VERSION 5.7 ;
  NOWIREEXTENSIONATPIN ON ;
  DIVIDERCHAR "/" ;
  BUSBITCHARS "[]" ;
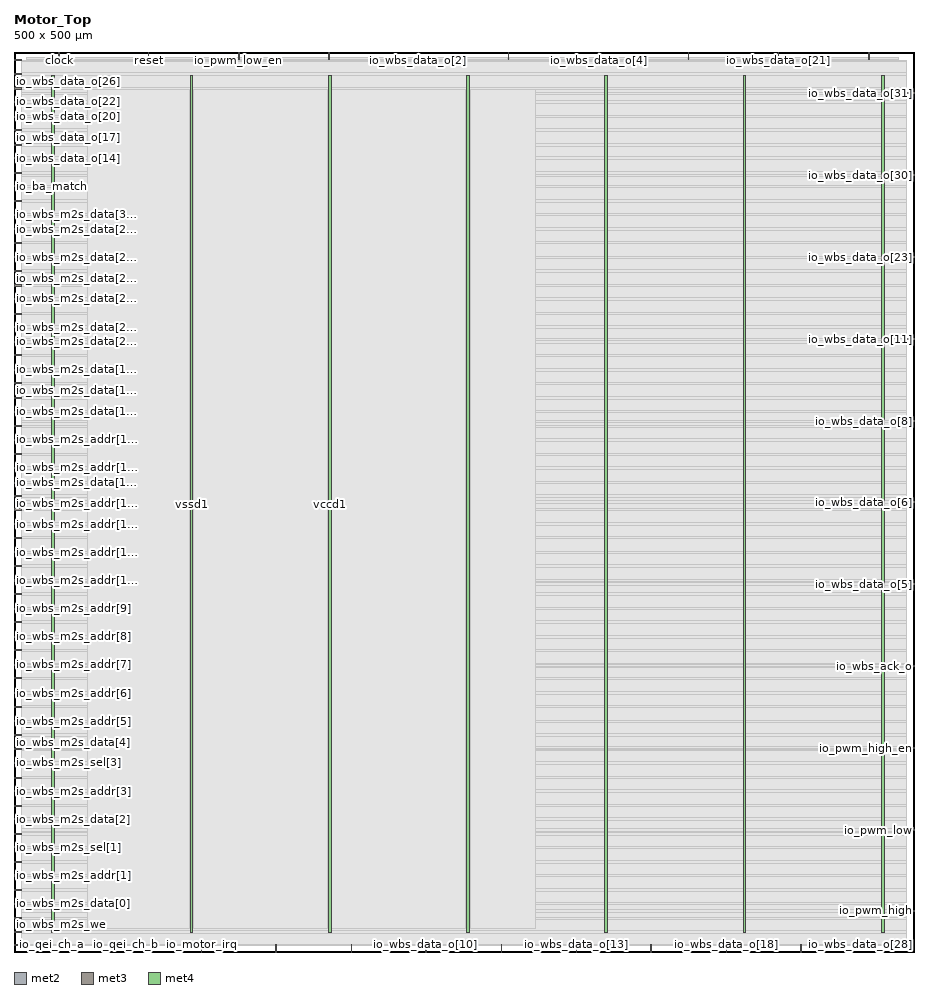
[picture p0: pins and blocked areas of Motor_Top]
MACRO Motor_Top
  CLASS BLOCK ;
  FOREIGN Motor_Top ;
  ORIGIN 0.000 0.000 ;
  SIZE 500.000 BY 500.000 ;
  PIN clock
    DIRECTION INPUT ;
    USE SIGNAL ;
    PORT
      LAYER met2 ;
        RECT 24.930 496.000 25.210 500.000 ;
    END
  END clock
  PIN io_ba_match
    DIRECTION INPUT ;
    USE SIGNAL ;
    PORT
      LAYER met3 ;
        RECT 0.000 425.040 4.000 425.640 ;
    END
  END io_ba_match
  PIN io_motor_irq
    DIRECTION OUTPUT TRISTATE ;
    USE SIGNAL ;
    PORT
      LAYER met2 ;
        RECT 104.050 0.000 104.330 4.000 ;
    END
  END io_motor_irq
  PIN io_pwm_high
    DIRECTION OUTPUT TRISTATE ;
    USE SIGNAL ;
    PORT
      LAYER met3 ;
        RECT 496.000 22.480 500.000 23.080 ;
    END
  END io_pwm_high
  PIN io_pwm_high_en
    DIRECTION OUTPUT TRISTATE ;
    USE SIGNAL ;
    PORT
      LAYER met3 ;
        RECT 496.000 112.920 500.000 113.520 ;
    END
  END io_pwm_high_en
  PIN io_pwm_low
    DIRECTION OUTPUT TRISTATE ;
    USE SIGNAL ;
    PORT
      LAYER met3 ;
        RECT 496.000 67.360 500.000 67.960 ;
    END
  END io_pwm_low
  PIN io_pwm_low_en
    DIRECTION OUTPUT TRISTATE ;
    USE SIGNAL ;
    PORT
      LAYER met2 ;
        RECT 124.750 496.000 125.030 500.000 ;
    END
  END io_pwm_low_en
  PIN io_qei_ch_a
    DIRECTION INPUT ;
    USE SIGNAL ;
    PORT
      LAYER met2 ;
        RECT 20.790 0.000 21.070 4.000 ;
    END
  END io_qei_ch_a
  PIN io_qei_ch_b
    DIRECTION INPUT ;
    USE SIGNAL ;
    PORT
      LAYER met2 ;
        RECT 62.190 0.000 62.470 4.000 ;
    END
  END io_qei_ch_b
  PIN io_wbs_ack_o
    DIRECTION OUTPUT TRISTATE ;
    USE SIGNAL ;
    PORT
      LAYER met3 ;
        RECT 496.000 158.480 500.000 159.080 ;
    END
  END io_wbs_ack_o
  PIN io_wbs_data_o[0]
    DIRECTION OUTPUT TRISTATE ;
    USE SIGNAL ;
    PORT
      LAYER met2 ;
        RECT 174.890 496.000 175.170 500.000 ;
    END
  END io_wbs_data_o[0]
  PIN io_wbs_data_o[10]
    DIRECTION OUTPUT TRISTATE ;
    USE SIGNAL ;
    PORT
      LAYER met2 ;
        RECT 228.710 0.000 228.990 4.000 ;
    END
  END io_wbs_data_o[10]
  PIN io_wbs_data_o[11]
    DIRECTION OUTPUT TRISTATE ;
    USE SIGNAL ;
    PORT
      LAYER met3 ;
        RECT 496.000 340.040 500.000 340.640 ;
    END
  END io_wbs_data_o[11]
  PIN io_wbs_data_o[12]
    DIRECTION OUTPUT TRISTATE ;
    USE SIGNAL ;
    PORT
      LAYER met2 ;
        RECT 270.570 0.000 270.850 4.000 ;
    END
  END io_wbs_data_o[12]
  PIN io_wbs_data_o[13]
    DIRECTION OUTPUT TRISTATE ;
    USE SIGNAL ;
    PORT
      LAYER met2 ;
        RECT 312.430 0.000 312.710 4.000 ;
    END
  END io_wbs_data_o[13]
  PIN io_wbs_data_o[14]
    DIRECTION OUTPUT TRISTATE ;
    USE SIGNAL ;
    PORT
      LAYER met3 ;
        RECT 0.000 440.680 4.000 441.280 ;
    END
  END io_wbs_data_o[14]
  PIN io_wbs_data_o[15]
    DIRECTION OUTPUT TRISTATE ;
    USE SIGNAL ;
    PORT
      LAYER met2 ;
        RECT 374.530 496.000 374.810 500.000 ;
    END
  END io_wbs_data_o[15]
  PIN io_wbs_data_o[16]
    DIRECTION OUTPUT TRISTATE ;
    USE SIGNAL ;
    PORT
      LAYER met2 ;
        RECT 353.830 0.000 354.110 4.000 ;
    END
  END io_wbs_data_o[16]
  PIN io_wbs_data_o[17]
    DIRECTION OUTPUT TRISTATE ;
    USE SIGNAL ;
    PORT
      LAYER met3 ;
        RECT 0.000 448.160 4.000 448.760 ;
    END
  END io_wbs_data_o[17]
  PIN io_wbs_data_o[18]
    DIRECTION OUTPUT TRISTATE ;
    USE SIGNAL ;
    PORT
      LAYER met2 ;
        RECT 395.690 0.000 395.970 4.000 ;
    END
  END io_wbs_data_o[18]
  PIN io_wbs_data_o[19]
    DIRECTION OUTPUT TRISTATE ;
    USE SIGNAL ;
    PORT
      LAYER met3 ;
        RECT 0.000 456.320 4.000 456.920 ;
    END
  END io_wbs_data_o[19]
  PIN io_wbs_data_o[1]
    DIRECTION OUTPUT TRISTATE ;
    USE SIGNAL ;
    PORT
      LAYER met3 ;
        RECT 0.000 432.520 4.000 433.120 ;
    END
  END io_wbs_data_o[1]
  PIN io_wbs_data_o[20]
    DIRECTION OUTPUT TRISTATE ;
    USE SIGNAL ;
    PORT
      LAYER met3 ;
        RECT 0.000 463.800 4.000 464.400 ;
    END
  END io_wbs_data_o[20]
  PIN io_wbs_data_o[21]
    DIRECTION OUTPUT TRISTATE ;
    USE SIGNAL ;
    PORT
      LAYER met2 ;
        RECT 424.670 496.000 424.950 500.000 ;
    END
  END io_wbs_data_o[21]
  PIN io_wbs_data_o[22]
    DIRECTION OUTPUT TRISTATE ;
    USE SIGNAL ;
    PORT
      LAYER met3 ;
        RECT 0.000 471.960 4.000 472.560 ;
    END
  END io_wbs_data_o[22]
  PIN io_wbs_data_o[23]
    DIRECTION OUTPUT TRISTATE ;
    USE SIGNAL ;
    PORT
      LAYER met3 ;
        RECT 496.000 385.600 500.000 386.200 ;
    END
  END io_wbs_data_o[23]
  PIN io_wbs_data_o[24]
    DIRECTION OUTPUT TRISTATE ;
    USE SIGNAL ;
    PORT
      LAYER met2 ;
        RECT 437.090 0.000 437.370 4.000 ;
    END
  END io_wbs_data_o[24]
  PIN io_wbs_data_o[25]
    DIRECTION OUTPUT TRISTATE ;
    USE SIGNAL ;
    PORT
      LAYER met3 ;
        RECT 0.000 479.440 4.000 480.040 ;
    END
  END io_wbs_data_o[25]
  PIN io_wbs_data_o[26]
    DIRECTION OUTPUT TRISTATE ;
    USE SIGNAL ;
    PORT
      LAYER met3 ;
        RECT 0.000 487.600 4.000 488.200 ;
    END
  END io_wbs_data_o[26]
  PIN io_wbs_data_o[27]
    DIRECTION OUTPUT TRISTATE ;
    USE SIGNAL ;
    PORT
      LAYER met3 ;
        RECT 0.000 495.080 4.000 495.680 ;
    END
  END io_wbs_data_o[27]
  PIN io_wbs_data_o[28]
    DIRECTION OUTPUT TRISTATE ;
    USE SIGNAL ;
    PORT
      LAYER met2 ;
        RECT 478.950 0.000 479.230 4.000 ;
    END
  END io_wbs_data_o[28]
  PIN io_wbs_data_o[29]
    DIRECTION OUTPUT TRISTATE ;
    USE SIGNAL ;
    PORT
      LAYER met2 ;
        RECT 474.810 496.000 475.090 500.000 ;
    END
  END io_wbs_data_o[29]
  PIN io_wbs_data_o[2]
    DIRECTION OUTPUT TRISTATE ;
    USE SIGNAL ;
    PORT
      LAYER met2 ;
        RECT 224.570 496.000 224.850 500.000 ;
    END
  END io_wbs_data_o[2]
  PIN io_wbs_data_o[30]
    DIRECTION OUTPUT TRISTATE ;
    USE SIGNAL ;
    PORT
      LAYER met3 ;
        RECT 496.000 431.160 500.000 431.760 ;
    END
  END io_wbs_data_o[30]
  PIN io_wbs_data_o[31]
    DIRECTION OUTPUT TRISTATE ;
    USE SIGNAL ;
    PORT
      LAYER met3 ;
        RECT 496.000 476.720 500.000 477.320 ;
    END
  END io_wbs_data_o[31]
  PIN io_wbs_data_o[3]
    DIRECTION OUTPUT TRISTATE ;
    USE SIGNAL ;
    PORT
      LAYER met2 ;
        RECT 274.710 496.000 274.990 500.000 ;
    END
  END io_wbs_data_o[3]
  PIN io_wbs_data_o[4]
    DIRECTION OUTPUT TRISTATE ;
    USE SIGNAL ;
    PORT
      LAYER met2 ;
        RECT 324.850 496.000 325.130 500.000 ;
    END
  END io_wbs_data_o[4]
  PIN io_wbs_data_o[5]
    DIRECTION OUTPUT TRISTATE ;
    USE SIGNAL ;
    PORT
      LAYER met3 ;
        RECT 496.000 204.040 500.000 204.640 ;
    END
  END io_wbs_data_o[5]
  PIN io_wbs_data_o[6]
    DIRECTION OUTPUT TRISTATE ;
    USE SIGNAL ;
    PORT
      LAYER met3 ;
        RECT 496.000 249.600 500.000 250.200 ;
    END
  END io_wbs_data_o[6]
  PIN io_wbs_data_o[7]
    DIRECTION OUTPUT TRISTATE ;
    USE SIGNAL ;
    PORT
      LAYER met2 ;
        RECT 145.450 0.000 145.730 4.000 ;
    END
  END io_wbs_data_o[7]
  PIN io_wbs_data_o[8]
    DIRECTION OUTPUT TRISTATE ;
    USE SIGNAL ;
    PORT
      LAYER met3 ;
        RECT 496.000 294.480 500.000 295.080 ;
    END
  END io_wbs_data_o[8]
  PIN io_wbs_data_o[9]
    DIRECTION OUTPUT TRISTATE ;
    USE SIGNAL ;
    PORT
      LAYER met2 ;
        RECT 187.310 0.000 187.590 4.000 ;
    END
  END io_wbs_data_o[9]
  PIN io_wbs_m2s_addr[0]
    DIRECTION INPUT ;
    USE SIGNAL ;
    PORT
      LAYER met3 ;
        RECT 0.000 18.400 4.000 19.000 ;
    END
  END io_wbs_m2s_addr[0]
  PIN io_wbs_m2s_addr[10]
    DIRECTION INPUT ;
    USE SIGNAL ;
    PORT
      LAYER met3 ;
        RECT 0.000 206.080 4.000 206.680 ;
    END
  END io_wbs_m2s_addr[10]
  PIN io_wbs_m2s_addr[11]
    DIRECTION INPUT ;
    USE SIGNAL ;
    PORT
      LAYER met3 ;
        RECT 0.000 221.720 4.000 222.320 ;
    END
  END io_wbs_m2s_addr[11]
  PIN io_wbs_m2s_addr[12]
    DIRECTION INPUT ;
    USE SIGNAL ;
    PORT
      LAYER met3 ;
        RECT 0.000 237.360 4.000 237.960 ;
    END
  END io_wbs_m2s_addr[12]
  PIN io_wbs_m2s_addr[13]
    DIRECTION INPUT ;
    USE SIGNAL ;
    PORT
      LAYER met3 ;
        RECT 0.000 253.000 4.000 253.600 ;
    END
  END io_wbs_m2s_addr[13]
  PIN io_wbs_m2s_addr[14]
    DIRECTION INPUT ;
    USE SIGNAL ;
    PORT
      LAYER met3 ;
        RECT 0.000 268.640 4.000 269.240 ;
    END
  END io_wbs_m2s_addr[14]
  PIN io_wbs_m2s_addr[15]
    DIRECTION INPUT ;
    USE SIGNAL ;
    PORT
      LAYER met3 ;
        RECT 0.000 284.280 4.000 284.880 ;
    END
  END io_wbs_m2s_addr[15]
  PIN io_wbs_m2s_addr[1]
    DIRECTION INPUT ;
    USE SIGNAL ;
    PORT
      LAYER met3 ;
        RECT 0.000 42.200 4.000 42.800 ;
    END
  END io_wbs_m2s_addr[1]
  PIN io_wbs_m2s_addr[2]
    DIRECTION INPUT ;
    USE SIGNAL ;
    PORT
      LAYER met3 ;
        RECT 0.000 65.320 4.000 65.920 ;
    END
  END io_wbs_m2s_addr[2]
  PIN io_wbs_m2s_addr[3]
    DIRECTION INPUT ;
    USE SIGNAL ;
    PORT
      LAYER met3 ;
        RECT 0.000 89.120 4.000 89.720 ;
    END
  END io_wbs_m2s_addr[3]
  PIN io_wbs_m2s_addr[4]
    DIRECTION INPUT ;
    USE SIGNAL ;
    PORT
      LAYER met3 ;
        RECT 0.000 112.240 4.000 112.840 ;
    END
  END io_wbs_m2s_addr[4]
  PIN io_wbs_m2s_addr[5]
    DIRECTION INPUT ;
    USE SIGNAL ;
    PORT
      LAYER met3 ;
        RECT 0.000 127.880 4.000 128.480 ;
    END
  END io_wbs_m2s_addr[5]
  PIN io_wbs_m2s_addr[6]
    DIRECTION INPUT ;
    USE SIGNAL ;
    PORT
      LAYER met3 ;
        RECT 0.000 143.520 4.000 144.120 ;
    END
  END io_wbs_m2s_addr[6]
  PIN io_wbs_m2s_addr[7]
    DIRECTION INPUT ;
    USE SIGNAL ;
    PORT
      LAYER met3 ;
        RECT 0.000 159.160 4.000 159.760 ;
    END
  END io_wbs_m2s_addr[7]
  PIN io_wbs_m2s_addr[8]
    DIRECTION INPUT ;
    USE SIGNAL ;
    PORT
      LAYER met3 ;
        RECT 0.000 174.800 4.000 175.400 ;
    END
  END io_wbs_m2s_addr[8]
  PIN io_wbs_m2s_addr[9]
    DIRECTION INPUT ;
    USE SIGNAL ;
    PORT
      LAYER met3 ;
        RECT 0.000 190.440 4.000 191.040 ;
    END
  END io_wbs_m2s_addr[9]
  PIN io_wbs_m2s_data[0]
    DIRECTION INPUT ;
    USE SIGNAL ;
    PORT
      LAYER met3 ;
        RECT 0.000 26.560 4.000 27.160 ;
    END
  END io_wbs_m2s_data[0]
  PIN io_wbs_m2s_data[10]
    DIRECTION INPUT ;
    USE SIGNAL ;
    PORT
      LAYER met3 ;
        RECT 0.000 214.240 4.000 214.840 ;
    END
  END io_wbs_m2s_data[10]
  PIN io_wbs_m2s_data[11]
    DIRECTION INPUT ;
    USE SIGNAL ;
    PORT
      LAYER met3 ;
        RECT 0.000 229.880 4.000 230.480 ;
    END
  END io_wbs_m2s_data[11]
  PIN io_wbs_m2s_data[12]
    DIRECTION INPUT ;
    USE SIGNAL ;
    PORT
      LAYER met3 ;
        RECT 0.000 245.520 4.000 246.120 ;
    END
  END io_wbs_m2s_data[12]
  PIN io_wbs_m2s_data[13]
    DIRECTION INPUT ;
    USE SIGNAL ;
    PORT
      LAYER met3 ;
        RECT 0.000 260.480 4.000 261.080 ;
    END
  END io_wbs_m2s_data[13]
  PIN io_wbs_m2s_data[14]
    DIRECTION INPUT ;
    USE SIGNAL ;
    PORT
      LAYER met3 ;
        RECT 0.000 276.120 4.000 276.720 ;
    END
  END io_wbs_m2s_data[14]
  PIN io_wbs_m2s_data[15]
    DIRECTION INPUT ;
    USE SIGNAL ;
    PORT
      LAYER met3 ;
        RECT 0.000 291.760 4.000 292.360 ;
    END
  END io_wbs_m2s_data[15]
  PIN io_wbs_m2s_data[16]
    DIRECTION INPUT ;
    USE SIGNAL ;
    PORT
      LAYER met3 ;
        RECT 0.000 299.920 4.000 300.520 ;
    END
  END io_wbs_m2s_data[16]
  PIN io_wbs_m2s_data[17]
    DIRECTION INPUT ;
    USE SIGNAL ;
    PORT
      LAYER met3 ;
        RECT 0.000 307.400 4.000 308.000 ;
    END
  END io_wbs_m2s_data[17]
  PIN io_wbs_m2s_data[18]
    DIRECTION INPUT ;
    USE SIGNAL ;
    PORT
      LAYER met3 ;
        RECT 0.000 315.560 4.000 316.160 ;
    END
  END io_wbs_m2s_data[18]
  PIN io_wbs_m2s_data[19]
    DIRECTION INPUT ;
    USE SIGNAL ;
    PORT
      LAYER met3 ;
        RECT 0.000 323.040 4.000 323.640 ;
    END
  END io_wbs_m2s_data[19]
  PIN io_wbs_m2s_data[1]
    DIRECTION INPUT ;
    USE SIGNAL ;
    PORT
      LAYER met3 ;
        RECT 0.000 49.680 4.000 50.280 ;
    END
  END io_wbs_m2s_data[1]
  PIN io_wbs_m2s_data[20]
    DIRECTION INPUT ;
    USE SIGNAL ;
    PORT
      LAYER met3 ;
        RECT 0.000 331.200 4.000 331.800 ;
    END
  END io_wbs_m2s_data[20]
  PIN io_wbs_m2s_data[21]
    DIRECTION INPUT ;
    USE SIGNAL ;
    PORT
      LAYER met3 ;
        RECT 0.000 338.680 4.000 339.280 ;
    END
  END io_wbs_m2s_data[21]
  PIN io_wbs_m2s_data[22]
    DIRECTION INPUT ;
    USE SIGNAL ;
    PORT
      LAYER met3 ;
        RECT 0.000 346.840 4.000 347.440 ;
    END
  END io_wbs_m2s_data[22]
  PIN io_wbs_m2s_data[23]
    DIRECTION INPUT ;
    USE SIGNAL ;
    PORT
      LAYER met3 ;
        RECT 0.000 354.320 4.000 354.920 ;
    END
  END io_wbs_m2s_data[23]
  PIN io_wbs_m2s_data[24]
    DIRECTION INPUT ;
    USE SIGNAL ;
    PORT
      LAYER met3 ;
        RECT 0.000 362.480 4.000 363.080 ;
    END
  END io_wbs_m2s_data[24]
  PIN io_wbs_m2s_data[25]
    DIRECTION INPUT ;
    USE SIGNAL ;
    PORT
      LAYER met3 ;
        RECT 0.000 369.960 4.000 370.560 ;
    END
  END io_wbs_m2s_data[25]
  PIN io_wbs_m2s_data[26]
    DIRECTION INPUT ;
    USE SIGNAL ;
    PORT
      LAYER met3 ;
        RECT 0.000 378.120 4.000 378.720 ;
    END
  END io_wbs_m2s_data[26]
  PIN io_wbs_m2s_data[27]
    DIRECTION INPUT ;
    USE SIGNAL ;
    PORT
      LAYER met3 ;
        RECT 0.000 385.600 4.000 386.200 ;
    END
  END io_wbs_m2s_data[27]
  PIN io_wbs_m2s_data[28]
    DIRECTION INPUT ;
    USE SIGNAL ;
    PORT
      LAYER met3 ;
        RECT 0.000 393.760 4.000 394.360 ;
    END
  END io_wbs_m2s_data[28]
  PIN io_wbs_m2s_data[29]
    DIRECTION INPUT ;
    USE SIGNAL ;
    PORT
      LAYER met3 ;
        RECT 0.000 401.240 4.000 401.840 ;
    END
  END io_wbs_m2s_data[29]
  PIN io_wbs_m2s_data[2]
    DIRECTION INPUT ;
    USE SIGNAL ;
    PORT
      LAYER met3 ;
        RECT 0.000 73.480 4.000 74.080 ;
    END
  END io_wbs_m2s_data[2]
  PIN io_wbs_m2s_data[30]
    DIRECTION INPUT ;
    USE SIGNAL ;
    PORT
      LAYER met3 ;
        RECT 0.000 409.400 4.000 410.000 ;
    END
  END io_wbs_m2s_data[30]
  PIN io_wbs_m2s_data[31]
    DIRECTION INPUT ;
    USE SIGNAL ;
    PORT
      LAYER met3 ;
        RECT 0.000 416.880 4.000 417.480 ;
    END
  END io_wbs_m2s_data[31]
  PIN io_wbs_m2s_data[3]
    DIRECTION INPUT ;
    USE SIGNAL ;
    PORT
      LAYER met3 ;
        RECT 0.000 96.600 4.000 97.200 ;
    END
  END io_wbs_m2s_data[3]
  PIN io_wbs_m2s_data[4]
    DIRECTION INPUT ;
    USE SIGNAL ;
    PORT
      LAYER met3 ;
        RECT 0.000 120.400 4.000 121.000 ;
    END
  END io_wbs_m2s_data[4]
  PIN io_wbs_m2s_data[5]
    DIRECTION INPUT ;
    USE SIGNAL ;
    PORT
      LAYER met3 ;
        RECT 0.000 136.040 4.000 136.640 ;
    END
  END io_wbs_m2s_data[5]
  PIN io_wbs_m2s_data[6]
    DIRECTION INPUT ;
    USE SIGNAL ;
    PORT
      LAYER met3 ;
        RECT 0.000 151.680 4.000 152.280 ;
    END
  END io_wbs_m2s_data[6]
  PIN io_wbs_m2s_data[7]
    DIRECTION INPUT ;
    USE SIGNAL ;
    PORT
      LAYER met3 ;
        RECT 0.000 167.320 4.000 167.920 ;
    END
  END io_wbs_m2s_data[7]
  PIN io_wbs_m2s_data[8]
    DIRECTION INPUT ;
    USE SIGNAL ;
    PORT
      LAYER met3 ;
        RECT 0.000 182.960 4.000 183.560 ;
    END
  END io_wbs_m2s_data[8]
  PIN io_wbs_m2s_data[9]
    DIRECTION INPUT ;
    USE SIGNAL ;
    PORT
      LAYER met3 ;
        RECT 0.000 198.600 4.000 199.200 ;
    END
  END io_wbs_m2s_data[9]
  PIN io_wbs_m2s_sel[0]
    DIRECTION INPUT ;
    USE SIGNAL ;
    PORT
      LAYER met3 ;
        RECT 0.000 34.040 4.000 34.640 ;
    END
  END io_wbs_m2s_sel[0]
  PIN io_wbs_m2s_sel[1]
    DIRECTION INPUT ;
    USE SIGNAL ;
    PORT
      LAYER met3 ;
        RECT 0.000 57.840 4.000 58.440 ;
    END
  END io_wbs_m2s_sel[1]
  PIN io_wbs_m2s_sel[2]
    DIRECTION INPUT ;
    USE SIGNAL ;
    PORT
      LAYER met3 ;
        RECT 0.000 80.960 4.000 81.560 ;
    END
  END io_wbs_m2s_sel[2]
  PIN io_wbs_m2s_sel[3]
    DIRECTION INPUT ;
    USE SIGNAL ;
    PORT
      LAYER met3 ;
        RECT 0.000 104.760 4.000 105.360 ;
    END
  END io_wbs_m2s_sel[3]
  PIN io_wbs_m2s_stb
    DIRECTION INPUT ;
    USE SIGNAL ;
    PORT
      LAYER met3 ;
        RECT 0.000 3.440 4.000 4.040 ;
    END
  END io_wbs_m2s_stb
  PIN io_wbs_m2s_we
    DIRECTION INPUT ;
    USE SIGNAL ;
    PORT
      LAYER met3 ;
        RECT 0.000 10.920 4.000 11.520 ;
    END
  END io_wbs_m2s_we
  PIN reset
    DIRECTION INPUT ;
    USE SIGNAL ;
    PORT
      LAYER met2 ;
        RECT 74.610 496.000 74.890 500.000 ;
    END
  END reset
  PIN vccd1
    DIRECTION INPUT ;
    USE POWER ;
    PORT
      LAYER met4 ;
        RECT 21.040 10.640 22.640 487.120 ;
    END
    PORT
      LAYER met4 ;
        RECT 174.640 10.640 176.240 487.120 ;
    END
    PORT
      LAYER met4 ;
        RECT 328.240 10.640 329.840 487.120 ;
    END
    PORT
      LAYER met4 ;
        RECT 481.840 10.640 483.440 487.120 ;
    END
  END vccd1
  PIN vssd1
    DIRECTION INPUT ;
    USE GROUND ;
    PORT
      LAYER met4 ;
        RECT 97.840 10.640 99.440 487.120 ;
    END
    PORT
      LAYER met4 ;
        RECT 251.440 10.640 253.040 487.120 ;
    END
    PORT
      LAYER met4 ;
        RECT 405.040 10.640 406.640 487.120 ;
    END
  END vssd1
  OBS
      LAYER li1 ;
        RECT 5.520 10.795 494.040 486.965 ;
      LAYER met1 ;
        RECT 5.520 10.640 494.040 487.120 ;
      LAYER met2 ;
        RECT 6.990 495.720 24.650 496.810 ;
        RECT 25.490 495.720 74.330 496.810 ;
        RECT 75.170 495.720 124.470 496.810 ;
        RECT 125.310 495.720 174.610 496.810 ;
        RECT 175.450 495.720 224.290 496.810 ;
        RECT 225.130 495.720 274.430 496.810 ;
        RECT 275.270 495.720 324.570 496.810 ;
        RECT 325.410 495.720 374.250 496.810 ;
        RECT 375.090 495.720 424.390 496.810 ;
        RECT 425.230 495.720 474.530 496.810 ;
        RECT 475.370 495.720 491.190 496.810 ;
        RECT 6.990 4.280 491.190 495.720 ;
        RECT 6.990 3.555 20.510 4.280 ;
        RECT 21.350 3.555 61.910 4.280 ;
        RECT 62.750 3.555 103.770 4.280 ;
        RECT 104.610 3.555 145.170 4.280 ;
        RECT 146.010 3.555 187.030 4.280 ;
        RECT 187.870 3.555 228.430 4.280 ;
        RECT 229.270 3.555 270.290 4.280 ;
        RECT 271.130 3.555 312.150 4.280 ;
        RECT 312.990 3.555 353.550 4.280 ;
        RECT 354.390 3.555 395.410 4.280 ;
        RECT 396.250 3.555 436.810 4.280 ;
        RECT 437.650 3.555 478.670 4.280 ;
        RECT 479.510 3.555 491.190 4.280 ;
      LAYER met3 ;
        RECT 4.400 494.680 496.000 495.545 ;
        RECT 4.000 488.600 496.000 494.680 ;
        RECT 4.400 487.200 496.000 488.600 ;
        RECT 4.000 480.440 496.000 487.200 ;
        RECT 4.400 479.040 496.000 480.440 ;
        RECT 4.000 477.720 496.000 479.040 ;
        RECT 4.000 476.320 495.600 477.720 ;
        RECT 4.000 472.960 496.000 476.320 ;
        RECT 4.400 471.560 496.000 472.960 ;
        RECT 4.000 464.800 496.000 471.560 ;
        RECT 4.400 463.400 496.000 464.800 ;
        RECT 4.000 457.320 496.000 463.400 ;
        RECT 4.400 455.920 496.000 457.320 ;
        RECT 4.000 449.160 496.000 455.920 ;
        RECT 4.400 447.760 496.000 449.160 ;
        RECT 4.000 441.680 496.000 447.760 ;
        RECT 4.400 440.280 496.000 441.680 ;
        RECT 4.000 433.520 496.000 440.280 ;
        RECT 4.400 432.160 496.000 433.520 ;
        RECT 4.400 432.120 495.600 432.160 ;
        RECT 4.000 430.760 495.600 432.120 ;
        RECT 4.000 426.040 496.000 430.760 ;
        RECT 4.400 424.640 496.000 426.040 ;
        RECT 4.000 417.880 496.000 424.640 ;
        RECT 4.400 416.480 496.000 417.880 ;
        RECT 4.000 410.400 496.000 416.480 ;
        RECT 4.400 409.000 496.000 410.400 ;
        RECT 4.000 402.240 496.000 409.000 ;
        RECT 4.400 400.840 496.000 402.240 ;
        RECT 4.000 394.760 496.000 400.840 ;
        RECT 4.400 393.360 496.000 394.760 ;
        RECT 4.000 386.600 496.000 393.360 ;
        RECT 4.400 385.200 495.600 386.600 ;
        RECT 4.000 379.120 496.000 385.200 ;
        RECT 4.400 377.720 496.000 379.120 ;
        RECT 4.000 370.960 496.000 377.720 ;
        RECT 4.400 369.560 496.000 370.960 ;
        RECT 4.000 363.480 496.000 369.560 ;
        RECT 4.400 362.080 496.000 363.480 ;
        RECT 4.000 355.320 496.000 362.080 ;
        RECT 4.400 353.920 496.000 355.320 ;
        RECT 4.000 347.840 496.000 353.920 ;
        RECT 4.400 346.440 496.000 347.840 ;
        RECT 4.000 341.040 496.000 346.440 ;
        RECT 4.000 339.680 495.600 341.040 ;
        RECT 4.400 339.640 495.600 339.680 ;
        RECT 4.400 338.280 496.000 339.640 ;
        RECT 4.000 332.200 496.000 338.280 ;
        RECT 4.400 330.800 496.000 332.200 ;
        RECT 4.000 324.040 496.000 330.800 ;
        RECT 4.400 322.640 496.000 324.040 ;
        RECT 4.000 316.560 496.000 322.640 ;
        RECT 4.400 315.160 496.000 316.560 ;
        RECT 4.000 308.400 496.000 315.160 ;
        RECT 4.400 307.000 496.000 308.400 ;
        RECT 4.000 300.920 496.000 307.000 ;
        RECT 4.400 299.520 496.000 300.920 ;
        RECT 4.000 295.480 496.000 299.520 ;
        RECT 4.000 294.080 495.600 295.480 ;
        RECT 4.000 292.760 496.000 294.080 ;
        RECT 4.400 291.360 496.000 292.760 ;
        RECT 4.000 285.280 496.000 291.360 ;
        RECT 4.400 283.880 496.000 285.280 ;
        RECT 4.000 277.120 496.000 283.880 ;
        RECT 4.400 275.720 496.000 277.120 ;
        RECT 4.000 269.640 496.000 275.720 ;
        RECT 4.400 268.240 496.000 269.640 ;
        RECT 4.000 261.480 496.000 268.240 ;
        RECT 4.400 260.080 496.000 261.480 ;
        RECT 4.000 254.000 496.000 260.080 ;
        RECT 4.400 252.600 496.000 254.000 ;
        RECT 4.000 250.600 496.000 252.600 ;
        RECT 4.000 249.200 495.600 250.600 ;
        RECT 4.000 246.520 496.000 249.200 ;
        RECT 4.400 245.120 496.000 246.520 ;
        RECT 4.000 238.360 496.000 245.120 ;
        RECT 4.400 236.960 496.000 238.360 ;
        RECT 4.000 230.880 496.000 236.960 ;
        RECT 4.400 229.480 496.000 230.880 ;
        RECT 4.000 222.720 496.000 229.480 ;
        RECT 4.400 221.320 496.000 222.720 ;
        RECT 4.000 215.240 496.000 221.320 ;
        RECT 4.400 213.840 496.000 215.240 ;
        RECT 4.000 207.080 496.000 213.840 ;
        RECT 4.400 205.680 496.000 207.080 ;
        RECT 4.000 205.040 496.000 205.680 ;
        RECT 4.000 203.640 495.600 205.040 ;
        RECT 4.000 199.600 496.000 203.640 ;
        RECT 4.400 198.200 496.000 199.600 ;
        RECT 4.000 191.440 496.000 198.200 ;
        RECT 4.400 190.040 496.000 191.440 ;
        RECT 4.000 183.960 496.000 190.040 ;
        RECT 4.400 182.560 496.000 183.960 ;
        RECT 4.000 175.800 496.000 182.560 ;
        RECT 4.400 174.400 496.000 175.800 ;
        RECT 4.000 168.320 496.000 174.400 ;
        RECT 4.400 166.920 496.000 168.320 ;
        RECT 4.000 160.160 496.000 166.920 ;
        RECT 4.400 159.480 496.000 160.160 ;
        RECT 4.400 158.760 495.600 159.480 ;
        RECT 4.000 158.080 495.600 158.760 ;
        RECT 4.000 152.680 496.000 158.080 ;
        RECT 4.400 151.280 496.000 152.680 ;
        RECT 4.000 144.520 496.000 151.280 ;
        RECT 4.400 143.120 496.000 144.520 ;
        RECT 4.000 137.040 496.000 143.120 ;
        RECT 4.400 135.640 496.000 137.040 ;
        RECT 4.000 128.880 496.000 135.640 ;
        RECT 4.400 127.480 496.000 128.880 ;
        RECT 4.000 121.400 496.000 127.480 ;
        RECT 4.400 120.000 496.000 121.400 ;
        RECT 4.000 113.920 496.000 120.000 ;
        RECT 4.000 113.240 495.600 113.920 ;
        RECT 4.400 112.520 495.600 113.240 ;
        RECT 4.400 111.840 496.000 112.520 ;
        RECT 4.000 105.760 496.000 111.840 ;
        RECT 4.400 104.360 496.000 105.760 ;
        RECT 4.000 97.600 496.000 104.360 ;
        RECT 4.400 96.200 496.000 97.600 ;
        RECT 4.000 90.120 496.000 96.200 ;
        RECT 4.400 88.720 496.000 90.120 ;
        RECT 4.000 81.960 496.000 88.720 ;
        RECT 4.400 80.560 496.000 81.960 ;
        RECT 4.000 74.480 496.000 80.560 ;
        RECT 4.400 73.080 496.000 74.480 ;
        RECT 4.000 68.360 496.000 73.080 ;
        RECT 4.000 66.960 495.600 68.360 ;
        RECT 4.000 66.320 496.000 66.960 ;
        RECT 4.400 64.920 496.000 66.320 ;
        RECT 4.000 58.840 496.000 64.920 ;
        RECT 4.400 57.440 496.000 58.840 ;
        RECT 4.000 50.680 496.000 57.440 ;
        RECT 4.400 49.280 496.000 50.680 ;
        RECT 4.000 43.200 496.000 49.280 ;
        RECT 4.400 41.800 496.000 43.200 ;
        RECT 4.000 35.040 496.000 41.800 ;
        RECT 4.400 33.640 496.000 35.040 ;
        RECT 4.000 27.560 496.000 33.640 ;
        RECT 4.400 26.160 496.000 27.560 ;
        RECT 4.000 23.480 496.000 26.160 ;
        RECT 4.000 22.080 495.600 23.480 ;
        RECT 4.000 19.400 496.000 22.080 ;
        RECT 4.400 18.000 496.000 19.400 ;
        RECT 4.000 11.920 496.000 18.000 ;
        RECT 4.400 10.520 496.000 11.920 ;
        RECT 4.000 4.440 496.000 10.520 ;
        RECT 4.400 3.575 496.000 4.440 ;
      LAYER met4 ;
        RECT 40.775 13.095 97.440 479.225 ;
        RECT 99.840 13.095 174.240 479.225 ;
        RECT 176.640 13.095 251.040 479.225 ;
        RECT 253.440 13.095 289.505 479.225 ;
  END
END Motor_Top
END LIBRARY

